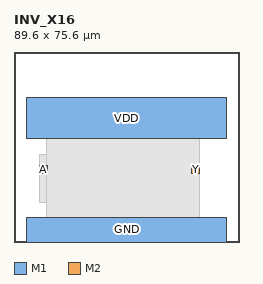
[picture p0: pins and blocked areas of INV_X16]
MACRO INV_X16
  CLASS CORE ;
  ORIGIN 0 0 ;
  SIZE 89.600 BY 75.600 ;
  SYMMETRY X Y ;
  SITE TR1um_access_site ;
  PIN VDD
    DIRECTION INOUT ;
    USE POWER ;
    PORT
      LAYER M1 ;
        RECT 5.000 41.000 84.600 57.600 ;
    END
  END VDD
  PIN GND
    DIRECTION INOUT ;
    USE GROUND ;
    PORT
      LAYER M1 ;
        RECT 5.000 0.000 84.600 9.800 ;
    END
  END GND
  PIN A
    DIRECTION INPUT ;
    USE SIGNAL ;
    PORT
      LAYER M2 ;
        RECT 10.100 27.100 13.500 30.500 ;
    END
  END A
  PIN Y
    DIRECTION OUTPUT ;
    USE SIGNAL ;
    PORT
      LAYER M2 ;
        RECT 70.600 27.100 74.000 30.500 ;
    END
  END Y
  OBS
    LAYER M1 ;
      RECT 10.100 15.900 67.500 34.900 ;
    LAYER M1 ;
      RECT 13.100 6.400 74.000 51.200 ;
    LAYER V1 ;
      RECT 11.100 28.100 12.500 29.500 ;
    LAYER V1 ;
      RECT 71.600 28.100 73.000 29.500 ;
  END
END INV_X16
